VERSION 5.7 ;
BUSBITCHARS "[]" ;
DIVIDERCHAR "/" ;

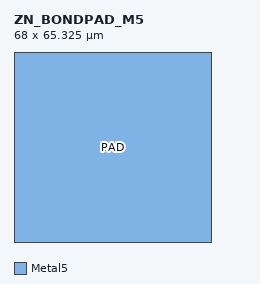
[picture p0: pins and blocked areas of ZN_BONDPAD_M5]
MACRO ZN_BONDPAD_M5
  CLASS BLOCK ;
  ORIGIN 0 0 ;
  SIZE 68.000 BY 65.325 ;
  SYMMETRY X Y ;
  PIN PAD
    DIRECTION INOUT ;
    USE SIGNAL ;
    PORT
      LAYER Metal5 ;
        RECT 0.000 0.000 68.000 65.325 ;
    END
  END PAD
END ZN_BONDPAD_M5

END LIBRARY
